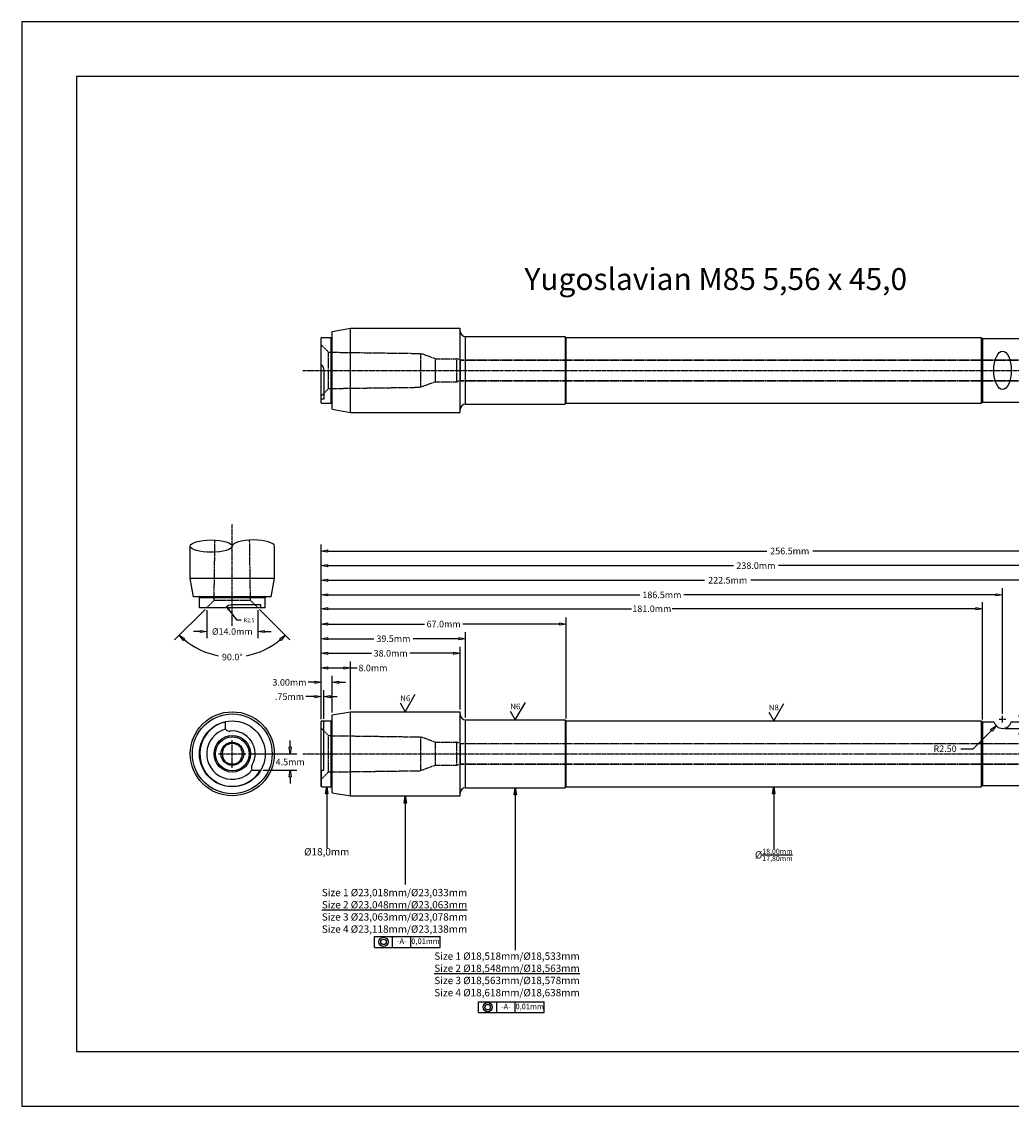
# Model space of a CAD drawing. Units: inches. Extents: x 0 to 420, y 0 to 297.
# Drawn here: x 0 to 271, y 0 to 297 of the extents above; entities that cross this region are included whole.
import ezdxf
from ezdxf.enums import TextEntityAlignment as Align

# ---------------------------------------------------------------- set-up
doc = ezdxf.new("R2010")
doc.units = ezdxf.units.IN
doc.header["$MEASUREMENT"] = 0
doc.linetypes.add('CENTER2', pattern=[1.125, 0.75, -0.125, 0.125, -0.125])
doc.linetypes.add('HIDDEN2', pattern=[0.1875, 0.125, -0.0625])
for name, color, linetype in [('CENTER', 1, 'CENTER2'), ('CENTERLINE', 1, 'CENTER2'), ('HIDDEN', 5, 'HIDDEN2'), ('TEXT', 5, 'Continuous')]:
    doc.layers.add(name, color=color, linetype=linetype)
doc.dimstyles.get("Standard").update_dxf_attribs({"dimscale": 10, "dimtxt": 0.18, "dimasz": 0.18, "dimexe": 0.18, "dimexo": 0.0625, "dimgap": 0.09, "dimtad": 0, "dimtih": 1, "dimtoh": 1, "dimdec": 4, "dimzin": 0, "dimdsep": 46, "dimtxsty": 'Standard', "dimblk": 'CLOSEDBLANK', "dimcen": 0.09, "dimadec": 4, "dimazin": 0, "dimtfac": 1, "dimtdec": 4, "dimtofl": 0, "dimtmove": 0, "dimatfit": 3, "dimldrblk": 'CLOSEDBLANK', "dimfxl": 0, "dimtolj": 1, "dimtzin": 0, "dimarcsym": 0})
doc.dimstyles.new('Standard$0', dxfattribs={"dimscale": 10, "dimtxt": 0.18, "dimasz": 0.18, "dimexe": 0.18, "dimexo": 0.0625, "dimgap": 0.09, "dimtad": 0, "dimtih": 1, "dimtoh": 1, "dimdec": 4, "dimzin": 4, "dimdsep": 46, "dimtxsty": 'Standard', "dimblk": 'CLOSEDBLANK', "dimcen": 0.09, "dimadec": 5, "dimazin": 1, "dimtfac": 1, "dimtdec": 4, "dimtofl": 0, "dimtmove": 0, "dimatfit": 3, "dimldrblk": 'CLOSEDBLANK', "dimfxl": 0, "dimtolj": 1, "dimtzin": 0, "dimarcsym": 0})

# ---------------------------------------------------------------- blocks, each defined once
blk = doc.blocks.new('_ClosedBlank')
at = {"color": 0, "linetype": 'ByBlock', "lineweight": -2}
for p, q in [((-1, 0.17), (0, 0)), ((-1, 0.17), (-1, -0.17)), ((0, 0), (-1, -0.17))]:
    blk.add_line(p, q, dxfattribs=at)
blk = doc.blocks.new('*D7')
at = {"color": 0, "lineweight": -2}
for p, q in [((80.2, 116.1), (78.4, 116.1)), ((82, 106.05), (82, 117.9)), ((85, 107.8), (85, 117.9)), ((86.8, 116.1), (88.6, 116.1))]:
    blk.add_line(p, q, dxfattribs=at)
at = {"layer": 'Defpoints', "color": 0}
for p in [(85, 116.1), (85, 107.18), (82, 105.43)]:
    blk.add_point(p, dxfattribs=at)
at = {"color": 0, "lineweight": -2, "xscale": 1.8, "yscale": 1.8, "zscale": 1.8}
blk.add_blockref('_ClosedBlank', (82, 116.1), dxfattribs=at)
at = {"color": 0, "lineweight": -2, "xscale": 1.8, "yscale": 1.8, "zscale": 1.8, "rotation": 180}
blk.add_blockref('_ClosedBlank', (85, 116.1), dxfattribs=at)
at = {"color": 0, "insert": (73.3, 116.1), "char_height": 1.8, "attachment_point": 5}
blk.add_mtext('\\A1;3.00mm', dxfattribs=at)
blk = doc.blocks.new('*D8')
at = {"color": 0, "lineweight": -2}
for p, q in [((82, 106.05), (82, 121.83)), ((90, 108.69), (90, 121.83)), ((83.8, 120.03), (88.2, 120.03)), ((90, 120.03), (91.8, 120.03))]:
    blk.add_line(p, q, dxfattribs=at)
at = {"layer": 'Defpoints', "color": 0}
for p in [(90, 120.03), (90, 108.06), (82, 105.43)]:
    blk.add_point(p, dxfattribs=at)
at = {"color": 0, "lineweight": -2, "xscale": 1.8, "yscale": 1.8, "zscale": 1.8, "rotation": 180}
blk.add_blockref('_ClosedBlank', (82, 120.03), dxfattribs=at)
at = {"color": 0, "lineweight": -2, "xscale": 1.8, "yscale": 1.8, "zscale": 1.8}
blk.add_blockref('_ClosedBlank', (90, 120.03), dxfattribs=at)
at = {"color": 0, "insert": (96.15, 120.03), "char_height": 1.8, "attachment_point": 5}
blk.add_mtext('\\A1;8.0mm', dxfattribs=at)
blk = doc.blocks.new('*D9')
at = {"color": 0, "lineweight": -2}
for p, q in [((82, 106.05), (82, 125.86)), ((120, 108.69), (120, 125.86)), ((83.8, 124.06), (95.75, 124.06)), ((118.2, 124.06), (106.25, 124.06))]:
    blk.add_line(p, q, dxfattribs=at)
at = {"layer": 'Defpoints', "color": 0}
for p in [(120, 124.06), (120, 108.06), (82, 105.43)]:
    blk.add_point(p, dxfattribs=at)
at = {"color": 0, "lineweight": -2, "xscale": 1.8, "yscale": 1.8, "zscale": 1.8, "rotation": 180}
blk.add_blockref('_ClosedBlank', (82, 124.06), dxfattribs=at)
at = {"color": 0, "lineweight": -2, "xscale": 1.8, "yscale": 1.8, "zscale": 1.8}
blk.add_blockref('_ClosedBlank', (120, 124.06), dxfattribs=at)
at = {"color": 0, "insert": (101, 124.06), "char_height": 1.8, "attachment_point": 5}
blk.add_mtext('\\A1;38.0mm', dxfattribs=at)
blk = doc.blocks.new('*D10')
at = {"color": 0, "lineweight": -2}
for p, q in [((82, 106.05), (82, 129.85)), ((83.8, 128.05), (96.35, 128.05)), ((119.7, 128.05), (107.15, 128.05)), ((121.5, 106.43), (121.5, 129.85))]:
    blk.add_line(p, q, dxfattribs=at)
at = {"layer": 'Defpoints', "color": 0}
for p in [(82, 128.05), (82, 105.43), (121.5, 105.8)]:
    blk.add_point(p, dxfattribs=at)
at = {"color": 0, "lineweight": -2, "xscale": 1.8, "yscale": 1.8, "zscale": 1.8, "rotation": 180}
blk.add_blockref('_ClosedBlank', (82, 128.05), dxfattribs=at)
at = {"color": 0, "lineweight": -2, "xscale": 1.8, "yscale": 1.8, "zscale": 1.8}
blk.add_blockref('_ClosedBlank', (121.5, 128.05), dxfattribs=at)
at = {"color": 0, "insert": (101.75, 128.05), "char_height": 1.8, "attachment_point": 5}
blk.add_mtext('\\A1;39.5mm', dxfattribs=at)
blk = doc.blocks.new('*D11')
at = {"color": 0, "lineweight": -2}
for p, q in [((82, 106.05), (82, 133.85)), ((149, 106.15), (149, 133.85)), ((83.8, 132.05), (110.25, 132.05)), ((147.2, 132.05), (120.75, 132.05))]:
    blk.add_line(p, q, dxfattribs=at)
at = {"layer": 'Defpoints', "color": 0}
for p in [(82, 132.05), (82, 105.43), (149, 105.53)]:
    blk.add_point(p, dxfattribs=at)
at = {"color": 0, "lineweight": -2, "xscale": 1.8, "yscale": 1.8, "zscale": 1.8, "rotation": 180}
blk.add_blockref('_ClosedBlank', (82, 132.05), dxfattribs=at)
at = {"color": 0, "lineweight": -2, "xscale": 1.8, "yscale": 1.8, "zscale": 1.8}
blk.add_blockref('_ClosedBlank', (149, 132.05), dxfattribs=at)
at = {"color": 0, "insert": (115.5, 132.05), "char_height": 1.8, "attachment_point": 5}
blk.add_mtext('\\A1;67.0mm', dxfattribs=at)
blk = doc.blocks.new('*D12')
at = {"color": 0, "lineweight": -2}
for p, q in [((82, 106.09), (82, 138.04)), ((263, 105.89), (263, 138.04)), ((83.8, 136.24), (166.95, 136.24)), ((261.2, 136.24), (178.05, 136.24))]:
    blk.add_line(p, q, dxfattribs=at)
at = {"layer": 'Defpoints', "color": 0}
for p in [(82, 136.24), (82, 105.47), (263, 105.27)]:
    blk.add_point(p, dxfattribs=at)
at = {"color": 0, "lineweight": -2, "xscale": 1.8, "yscale": 1.8, "zscale": 1.8, "rotation": 180}
blk.add_blockref('_ClosedBlank', (82, 136.24), dxfattribs=at)
at = {"color": 0, "lineweight": -2, "xscale": 1.8, "yscale": 1.8, "zscale": 1.8}
blk.add_blockref('_ClosedBlank', (263, 136.24), dxfattribs=at)
at = {"color": 0, "insert": (172.5, 136.24), "char_height": 1.8, "attachment_point": 5}
blk.add_mtext('\\A1;181.0mm', dxfattribs=at)
blk = doc.blocks.new('*D13')
at = {"color": 0, "lineweight": -2}
for p, q in [((82, 106.05), (82, 141.85)), ((83.8, 140.05), (169.25, 140.05)), ((266.7, 140.05), (181.25, 140.05)), ((268.5, 107.47), (268.5, 141.85))]:
    blk.add_line(p, q, dxfattribs=at)
at = {"layer": 'Defpoints', "color": 0}
for p in [(82, 140.05), (82, 105.43), (268.5, 106.85)]:
    blk.add_point(p, dxfattribs=at)
at = {"color": 0, "lineweight": -2, "xscale": 1.8, "yscale": 1.8, "zscale": 1.8, "rotation": 180}
blk.add_blockref('_ClosedBlank', (82, 140.05), dxfattribs=at)
at = {"color": 0, "lineweight": -2, "xscale": 1.8, "yscale": 1.8, "zscale": 1.8}
blk.add_blockref('_ClosedBlank', (268.5, 140.05), dxfattribs=at)
at = {"color": 0, "insert": (175.25, 140.05), "char_height": 1.8, "attachment_point": 5}
blk.add_mtext('\\A1;186.5mm', dxfattribs=at)
blk = doc.blocks.new('*D14')
at = {"color": 0, "lineweight": -2}
for p, q in [((82, 106.05), (82, 145.85)), ((304.5, 105.89), (304.5, 145.85)), ((83.8, 144.05), (186.95, 144.05)), ((302.7, 144.05), (199.55, 144.05))]:
    blk.add_line(p, q, dxfattribs=at)
at = {"layer": 'Defpoints', "color": 0}
for p in [(82, 144.05), (82, 105.43), (304.5, 105.27)]:
    blk.add_point(p, dxfattribs=at)
at = {"color": 0, "lineweight": -2, "xscale": 1.8, "yscale": 1.8, "zscale": 1.8, "rotation": 180}
blk.add_blockref('_ClosedBlank', (82, 144.05), dxfattribs=at)
at = {"color": 0, "lineweight": -2, "xscale": 1.8, "yscale": 1.8, "zscale": 1.8}
blk.add_blockref('_ClosedBlank', (304.5, 144.05), dxfattribs=at)
at = {"color": 0, "insert": (193.25, 144.05), "char_height": 1.8, "attachment_point": 5}
blk.add_mtext('\\A1;222.5mm', dxfattribs=at)
blk = doc.blocks.new('*D17')
at = {"color": 0, "lineweight": -2}
for p, q in [((82, 106.05), (82, 113.98)), ((82.75, 106.06), (82.75, 113.98)), ((80.2, 112.18), (77.8, 112.18)), ((84.55, 112.18), (86.35, 112.18))]:
    blk.add_line(p, q, dxfattribs=at)
at = {"layer": 'Defpoints', "color": 0}
for p in [(82.75, 112.18), (82, 105.43), (82.75, 105.43)]:
    blk.add_point(p, dxfattribs=at)
at = {"color": 0, "lineweight": -2, "xscale": 1.8, "yscale": 1.8, "zscale": 1.8}
blk.add_blockref('_ClosedBlank', (82, 112.18), dxfattribs=at)
at = {"color": 0, "lineweight": -2, "xscale": 1.8, "yscale": 1.8, "zscale": 1.8, "rotation": 180}
blk.add_blockref('_ClosedBlank', (82.75, 112.18), dxfattribs=at)
at = {"color": 0, "insert": (73.3, 112.18), "char_height": 1.8, "attachment_point": 5}
blk.add_mtext('\\A1;.75mm', dxfattribs=at)
blk = doc.blocks.new('*D18')
at = {"color": 0, "lineweight": -2}
for p, q in [((73.5, 98.33), (73.5, 100.13)), ((62.08, 96.53), (75.3, 96.53)), ((66.07, 92.03), (75.3, 92.03)), ((73.5, 90.23), (73.5, 88.43))]:
    blk.add_line(p, q, dxfattribs=at)
at = {"layer": 'Defpoints', "color": 0}
for p in [(61.46, 96.53), (73.5, 96.53), (65.44, 92.03)]:
    blk.add_point(p, dxfattribs=at)
at = {"color": 0, "lineweight": -2, "xscale": 1.8, "yscale": 1.8, "zscale": 1.8}
for p, rotation in [((73.5, 96.53), 270), ((73.5, 92.03), 90)]:
    blk.add_blockref('_ClosedBlank', p, dxfattribs=dict(at, rotation=rotation))
at = {"color": 0, "insert": (73.5, 94.28), "char_height": 1.8, "attachment_point": 5}
blk.add_mtext('\\A1;4.5mm', dxfattribs=at)
blk = doc.blocks.new('*D19')
at = {"color": 0, "lineweight": -2}
for p, q in [((58.99, 133.09), (56.78, 135.95)), ((60.07, 133.09), (58.99, 133.09))]:
    blk.add_line(p, q, dxfattribs=at)
at = {"layer": 'Defpoints', "color": 0}
for p in [(56.12, 136.8), (57.65, 134.83)]:
    blk.add_point(p, dxfattribs=at)
at = {"color": 0, "lineweight": -2, "xscale": 1.08, "yscale": 1.08, "zscale": 1.08, "rotation": 127.7379653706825}
blk.add_blockref('_ClosedBlank', (56.12, 136.8), dxfattribs=at)
at = {"color": 0, "insert": (62.23, 133.09), "char_height": 1.08, "attachment_point": 5}
blk.add_mtext('\\A1;R2.5', dxfattribs=at)
blk = doc.blocks.new('*D22')
at = {"color": 0, "lineweight": -2}
for p, q in [((82, 106.05), (82, 149.85)), ((319.98, 106.18), (319.98, 149.85)), ((83.8, 148.05), (194.84, 148.05)), ((318.18, 148.05), (207.14, 148.05))]:
    blk.add_line(p, q, dxfattribs=at)
at = {"layer": 'Defpoints', "color": 0}
for p in [(82, 148.05), (82, 105.43), (319.98, 105.55)]:
    blk.add_point(p, dxfattribs=at)
at = {"color": 0, "lineweight": -2, "xscale": 1.8, "yscale": 1.8, "zscale": 1.8, "rotation": 180}
blk.add_blockref('_ClosedBlank', (82, 148.05), dxfattribs=at)
at = {"color": 0, "lineweight": -2, "xscale": 1.8, "yscale": 1.8, "zscale": 1.8}
blk.add_blockref('_ClosedBlank', (319.98, 148.05), dxfattribs=at)
at = {"color": 0, "insert": (200.99, 148.05), "char_height": 1.8, "attachment_point": 5}
blk.add_mtext('\\A1;238.0mm', dxfattribs=at)
blk = doc.blocks.new('*D23')
at = {"color": 0, "lineweight": -2}
for p, q in [((273.39, 107.07), (273.39, 113.24)), ((273.39, 113.24), (275.19, 113.24)), ((271.66, 105.27), (275.19, 105.27)), ((269.12, 103.49), (275.19, 103.49)), ((273.39, 101.69), (273.39, 99.89))]:
    blk.add_line(p, q, dxfattribs=at)
at = {"layer": 'Defpoints', "color": 0}
for p in [(271.04, 105.27), (273.39, 105.27), (268.5, 103.49)]:
    blk.add_point(p, dxfattribs=at)
at = {"color": 0, "lineweight": -2, "xscale": 1.8, "yscale": 1.8, "zscale": 1.8}
for p, rotation in [((273.39, 105.27), 270), ((273.39, 103.49), 90)]:
    blk.add_blockref('_ClosedBlank', p, dxfattribs=dict(at, rotation=rotation))
at = {"color": 0, "insert": (280.29, 113.24), "char_height": 1.8, "attachment_point": 5}
blk.add_mtext('\\A1;1.78mm', dxfattribs=at)
blk = doc.blocks.new('*D24')
at = {"color": 0, "lineweight": -2}
for p, q in [((260.42, 97.91), (265.46, 102.95)), ((257.12, 97.91), (260.42, 97.91))]:
    blk.add_line(p, q, dxfattribs=at)
at = {"layer": 'Defpoints', "color": 0}
for p in [(266.73, 104.22), (268.5, 105.99)]:
    blk.add_point(p, dxfattribs=at)
at = {"color": 0, "lineweight": -2, "xscale": 1.8, "yscale": 1.8, "zscale": 1.8, "rotation": 44.99999999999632}
blk.add_blockref('_ClosedBlank', (266.73, 104.22), dxfattribs=at)
at = {"color": 0, "insert": (252.77, 97.91), "char_height": 1.8, "attachment_point": 5}
blk.add_mtext('\\A1;R2.50', dxfattribs=at)
blk = doc.blocks.new('*D25')
at = {"color": 0, "lineweight": -2}
for p, q in [((82, 106.05), (82, 153.85)), ((83.8, 152.05), (203.95, 152.05)), ((336.7, 152.05), (216.55, 152.05)), ((338.5, 104.18), (338.5, 153.85))]:
    blk.add_line(p, q, dxfattribs=at)
at = {"layer": 'Defpoints', "color": 0}
for p in [(82, 152.05), (82, 105.43), (338.5, 103.55)]:
    blk.add_point(p, dxfattribs=at)
at = {"color": 0, "lineweight": -2, "xscale": 1.8, "yscale": 1.8, "zscale": 1.8, "rotation": 180}
blk.add_blockref('_ClosedBlank', (82, 152.05), dxfattribs=at)
at = {"color": 0, "lineweight": -2, "xscale": 1.8, "yscale": 1.8, "zscale": 1.8}
blk.add_blockref('_ClosedBlank', (338.5, 152.05), dxfattribs=at)
at = {"color": 0, "insert": (210.25, 152.05), "char_height": 1.8, "attachment_point": 5}
blk.add_mtext('\\A1;256.5mm', dxfattribs=at)
blk = doc.blocks.new('*D26')
at = {"color": 0, "lineweight": -2}
for p, q in [((50.65, 135.9), (50.65, 128.21)), ((64.65, 135.9), (64.65, 128.21)), ((48.85, 130.01), (47.05, 130.01)), ((66.45, 130.01), (68.25, 130.01))]:
    blk.add_line(p, q, dxfattribs=at)
at = {"layer": 'Defpoints', "color": 0}
for p in [(50.65, 136.53), (64.65, 136.53), (64.65, 130.01)]:
    blk.add_point(p, dxfattribs=at)
at = {"color": 0, "lineweight": -2, "xscale": 1.8, "yscale": 1.8, "zscale": 1.8}
blk.add_blockref('_ClosedBlank', (50.65, 130.01), dxfattribs=at)
at = {"color": 0, "lineweight": -2, "xscale": 1.8, "yscale": 1.8, "zscale": 1.8, "rotation": 180}
blk.add_blockref('_ClosedBlank', (64.65, 130.01), dxfattribs=at)
at = {"color": 0, "insert": (57.65, 130.01), "char_height": 1.8, "attachment_point": 5}
blk.add_mtext('\\A1;%%C14.0mm', dxfattribs=at)
blk = doc.blocks.new('*D27')
at = {"color": 0, "lineweight": -2}
for p, q in [((50.21, 136.08), (41.87, 127.75)), ((65.09, 136.08), (73.43, 127.75))]:
    blk.add_line(p, q, dxfattribs=at)
for start, end in [(230.0298, 259.0388), (280.9612, 309.9702)]:
    blk.add_arc((57.65, 143.53), 20.51, start, end, dxfattribs=at)
at = {"layer": 'Defpoints', "color": 0}
for p in [(52.67, 138.55), (62.63, 138.55), (50.65, 136.53), (64.65, 136.53), (52.34, 123.71)]:
    blk.add_point(p, dxfattribs=at)
at = {"color": 0, "lineweight": -2, "xscale": 1.8, "yscale": 1.8, "zscale": 1.8}
for p, rotation in [((43.15, 129.02), 137.5149116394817), ((72.15, 129.02), 42.48508836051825)]:
    blk.add_blockref('_ClosedBlank', p, dxfattribs=dict(at, rotation=rotation))
at = {"color": 0, "insert": (57.65, 123.01), "char_height": 1.8, "attachment_point": 5}
blk.add_mtext('\\A1;90.0°', dxfattribs=at)

msp = doc.modelspace()

# ---------------------------------------------------------------- linework, layer by layer
for p, q in [((84.99996, 212.17839), (89.99996, 213.06003)), ((84.99996, 190.87166), (84.99996, 212.17839)), ((89.99996, 213.06003), (119.99996, 213.06003)), ((89.99996, 189.99003), (89.99996, 213.06003)), ((119.99996, 189.99003), (119.99996, 213.06003)), ((81.99996, 192.62503), (81.99996, 210.42503)), ((82.09996, 210.52503), (84.74996, 210.52503)), ((84.74996, 192.52503), (84.74996, 210.52503)), ((121.49996, 192.25003), (121.49996, 210.80003)), ((121.49996, 210.80003), (148.74996, 210.80003)), ((148.74996, 210.80003), (148.74996, 192.25003)), ((148.99996, 210.52503), (262.75121, 210.52503)), ((148.99996, 192.52503), (148.99996, 210.52503)), ((262.75121, 192.52503), (262.75121, 210.52503)), ((263.00121, 210.22503), (263.00121, 192.82503)), ((263.00121, 210.22503), (304.49996, 210.22503)), ((82.79996, 193.7308), (82.79996, 201.52503)), ((81.99996, 193.7308), (82.79996, 193.7308)), ((82.09996, 192.52503), (84.74996, 192.52503)), ((84.99996, 190.87166), (89.99996, 189.99003)), ((121.49996, 192.25003), (148.74996, 192.25003)), ((148.99996, 192.52503), (262.75121, 192.52503)), ((263.00121, 192.82503), (304.49996, 192.82503)), ((89.99996, 189.99003), (119.99996, 189.99003)), ((46.11496, 144.52503), (46.11496, 153.39189)), ((69.18496, 144.52503), (69.18496, 153.39189)), ((69.18496, 144.52503), (46.11496, 144.52503)), ((46.9966, 139.52503), (46.11496, 144.52503)), ((68.30333, 139.52503), (69.18496, 144.52503)), ((68.30333, 139.52503), (46.9966, 139.52503)), ((48.64996, 136.62503), (48.64996, 139.27503)), ((66.64996, 139.27503), (48.64996, 139.27503)), ((65.44419, 137.32503), (57.64996, 137.32503)), ((65.44419, 136.52503), (65.44419, 137.32503)), ((66.64996, 136.62503), (66.64996, 139.27503)), ((66.54996, 136.52503), (48.74996, 136.52503)), ((103.62514, 110.44128), (104.99996, 108.06003)), ((104.99996, 108.06003), (107.74959, 112.82253)), ((135.12496, 105.80003), (137.87459, 110.56253)), ((205.87559, 105.52503), (208.62522, 110.28753)), ((84.99996, 107.17839), (89.99996, 108.06003)), ((84.99996, 85.87166), (84.99996, 107.17839)), ((89.99996, 108.06003), (119.99996, 108.06003)), ((89.99996, 84.99003), (89.99996, 108.06003)), ((119.99996, 84.99003), (119.99996, 108.06003)), ((133.75015, 108.18128), (135.12496, 105.80003)), ((204.50077, 107.90628), (205.87559, 105.52503)), ((55.81693, 103.28077), (55.81693, 105.30811)), ((81.99996, 87.62503), (81.99996, 105.42503)), ((82.09996, 105.52503), (84.74996, 105.52503)), ((82.74996, 92.02503), (82.74996, 105.43705)), ((84.74996, 87.52503), (84.74996, 105.52503)), ((121.49996, 87.25003), (121.49996, 105.80003)), ((121.49996, 105.80003), (148.74996, 105.80003)), ((148.74996, 105.80003), (148.74996, 87.25003)), ((148.99996, 105.52503), (262.75121, 105.52503)), ((148.99996, 87.52503), (148.99996, 105.52503)), ((262.75121, 87.52503), (262.75121, 105.52503)), ((263.00121, 105.26503), (263.00121, 87.82503)), ((263.00121, 105.26503), (266.10649, 105.26503)), ((270.89343, 105.26503), (304.49996, 105.26503)), ((82.74996, 102.77503), (81.99996, 103.52503)), ((63.01186, 92.02503), (65.44419, 92.02503)), ((81.99996, 92.02503), (82.74996, 92.02503)), ((82.09996, 87.52503), (82.09996, 92.02503)), ((82.09996, 87.52503), (84.74996, 87.52503)), ((121.49996, 87.25003), (148.74996, 87.25003)), ((148.99996, 87.52503), (262.75121, 87.52503)), ((263.00121, 87.82503), (304.49996, 87.82503)), ((84.99996, 85.87166), (89.99996, 84.99003)), ((89.99996, 84.99003), (119.99996, 84.99003))]:
    msp.add_line(p, q)
for points in [[(0, 0), (420, 0), (420, 297), (0, 297)], [(15, 15), (405, 15), (405, 282), (15, 282)]]:
    msp.add_lwpolyline(points, close=True)
for radius in [11.5, 10.9211, 9, 5.0063, 4.625, 3.145]:
    msp.add_circle((57.64996, 96.52503), radius)
for centre, radius, start, end in [((121.49996, 212.30003), 1.5, 180, 270), ((82.09996, 210.42503), 0.1, 90, 180), ((84.74996, 210.77503), 0.25, 270, 0), ((148.99996, 210.77503), 0.25, 180, 270), ((263.00121, 210.47503), 0.25, 180, 270), ((80.79996, 201.52503), 2, 0, 53.1301024), ((82.09996, 192.62503), 0.1, 180, 270), ((84.74996, 192.27503), 0.25, 0, 90), ((121.49996, 190.75003), 1.5, 90, 180), ((148.99996, 192.27503), 0.25, 90, 180), ((263.00121, 192.57503), 0.25, 90, 180), ((48.39996, 139.27503), 0.25, 0, 90), ((48.74996, 136.62503), 0.1, 180, 270), ((57.64996, 134.82503), 2.5, 90, 137.156357), ((66.54996, 136.62503), 0.1, 270, 360), ((66.89996, 139.27503), 0.25, 90, 180), ((121.49996, 107.30003), 1.5, 180, 270), ((57.64996, 96.52503), 8.9, 101.885612, 329.6276163), ((82.09996, 105.42503), 0.1, 90, 180), ((84.74996, 105.77503), 0.25, 270, 0), ((148.99996, 105.77503), 0.25, 180, 270), ((263.00121, 105.51503), 0.25, 180, 270), ((268.49996, 105.98703), 2.5, 196.7861274, 343.2138726), ((57.64996, 96.52503), 7, 105.1805438, 319.9947991), ((56.92145, 104.13582), 1.39681, 217.7449003, 277.6444066), ((57.64996, 96.52503), 6.25, 330.7, 95.9540752), ((57.64996, 96.52503), 2.85, 119.723042, 150.2785778), ((56.28649, 98.91322), 0.1, 46.1895335, 119.723042), ((57.64996, 96.52503), 2.78, 62.2554388, 117.7461811), ((59.01336, 98.91326), 0.1, 60.2785778, 133.8120863), ((57.64996, 96.52503), 2.85, 29.723042, 60.2785778), ((57.64996, 96.52503), 2.78, 152.2554388, 207.7461811), ((55.26173, 97.88843), 0.1, 150.2785778, 223.8120863), ((55.26177, 95.16156), 0.1, 136.1895335, 209.723042), ((57.64996, 96.52503), 2.85, 209.723042, 240.2785778), ((57.64996, 96.52503), 2.85, 299.723042, 330.2785778), ((60.03815, 97.8885), 0.1, 316.1895335, 29.723042), ((57.64996, 96.52503), 2.78, 332.2554388, 27.7461811), ((60.03819, 95.16162), 0.1, 330.2785778, 43.8120863), ((56.28656, 94.1368), 0.1, 240.2785778, 313.8120863), ((57.64996, 96.52503), 2.78, 242.2554388, 297.7461811), ((59.01343, 94.13684), 0.1, 226.1895335, 299.723042), ((64.2927, 92.67096), 1.43329, 146.2913703, 206.7411104), ((82.09996, 87.62503), 0.1, 180, 270), ((84.74996, 87.27503), 0.25, 0, 90), ((121.49996, 85.75003), 1.5, 90, 180), ((148.99996, 87.27503), 0.25, 90, 180), ((263.00121, 87.57503), 0.25, 90, 180)]:
    msp.add_arc(centre, radius, start, end)
for centre, major_axis, ratio in [((268.49996, 201.52503), (0, -5.2703), 0.454143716), ((51.88246, 153.39189), (-5.7675, 0), 0.291449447)]:
    msp.add_ellipse(centre, major_axis=major_axis, ratio=ratio)
for centre, major_axis, ratio, start_param, end_param in [((63.41746, 153.39189), (-5.7675, 0), 0.291449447, 3.141592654, 6.283185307), ((81.99996, 105.43079), (0.75041, 0.00318), 0.126149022, -0.033582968, 1.436603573)]:
    msp.add_ellipse(centre, major_axis=major_axis, ratio=ratio, start_param=start_param, end_param=end_param)
at = {"layer": 'CENTER'}
for p, q in [((267.59996, 105.98703), (269.39996, 105.98703)), ((268.49996, 105.08703), (268.49996, 106.88703))]:
    msp.add_line(p, q, dxfattribs=at)
at = {"layer": 'CENTERLINE'}
for p, q in [((76.99996, 201.52503), (343.49996, 201.52503)), ((57.64996, 131.52503), (57.64996, 159.42228)), ((57.64996, 92.71503), (57.64996, 100.33503)), ((53.83996, 96.52503), (61.45996, 96.52503)), ((76.99996, 96.52503), (343.49996, 96.52503))]:
    msp.add_line(p, q, dxfattribs=at)
at = {"layer": 'HIDDEN'}
for p, q in [((81.99996, 208.52503), (84.02196, 206.50302)), ((84.02196, 206.50303), (109.24996, 206.15003)), ((84.02196, 196.54703), (84.02196, 206.50303)), ((109.24996, 196.90017), (109.24996, 206.15003)), ((113.24997, 204.67003), (109.25001, 206.15002)), ((113.24997, 204.67003), (119.06996, 204.67003)), ((113.24997, 198.25204), (113.24997, 204.67002)), ((119.06996, 198.38003), (119.06996, 204.67003)), ((120.13754, 204.37503), (119.06996, 204.67003)), ((120.13754, 198.67503), (120.13754, 204.37503)), ((120.13754, 204.37503), (338.49996, 204.37503)), ((120.13754, 204.30503), (338.49996, 204.30503)), ((81.99996, 194.52503), (84.02196, 196.54703)), ((84.02196, 196.54703), (109.24998, 196.90017)), ((113.24997, 198.38003), (109.25001, 196.90004)), ((113.24997, 198.38003), (119.06996, 198.38003)), ((120.13754, 198.67503), (119.06999, 198.3799)), ((120.13754, 198.74503), (338.49996, 198.74503)), ((120.13754, 198.67503), (338.49996, 198.67503)), ((52.67196, 138.54703), (52.90282, 155.04631)), ((62.62796, 138.54703), (62.397, 155.0463)), ((50.64996, 136.52503), (52.67196, 138.54703)), ((62.62796, 138.54703), (52.67196, 138.54703)), ((64.64996, 136.52503), (62.62796, 138.54703)), ((82.74996, 102.77503), (84.02196, 101.50302)), ((84.02196, 101.50303), (109.24996, 101.15003)), ((84.02196, 91.54703), (84.02196, 101.50303)), ((109.24996, 91.90017), (109.24996, 101.15003)), ((113.24997, 99.67003), (109.25001, 101.15002)), ((113.24997, 99.67003), (119.06996, 99.67003)), ((113.24997, 93.25204), (113.24997, 99.67002)), ((119.06996, 93.38003), (119.06996, 99.67003)), ((120.13754, 99.37503), (119.06996, 99.67003)), ((120.13754, 93.67503), (120.13754, 99.37503)), ((120.13754, 99.37503), (338.49996, 99.37503)), ((120.13754, 99.30503), (338.49996, 99.30503)), ((113.24997, 93.38003), (109.25001, 91.90004)), ((113.24997, 93.38003), (119.06996, 93.38003)), ((120.13754, 93.67503), (119.06999, 93.3799)), ((120.13754, 93.74503), (338.49996, 93.74503)), ((120.13754, 93.67503), (338.49996, 93.67503)), ((81.99996, 89.52503), (84.02196, 91.54703)), ((84.02196, 91.54703), (109.24998, 91.90017))]:
    msp.add_line(p, q, dxfattribs=at)
for p in [(119.06996, 204.67003), (119.06996, 198.38003), (119.06996, 99.67003), (119.06996, 93.38003)]:
    msp.add_point(p, dxfattribs=at)
at = {"layer": 'TEXT', "color": 7}
for p, q in [((96.5396, 43.525), (96.5396, 46.525)), ((96.5396, 46.525), (101.5396, 46.525)), ((101.5396, 46.525), (106.5396, 46.525)), ((101.5396, 43.525), (101.5396, 46.525)), ((106.5396, 46.525), (114.5396, 46.525)), ((106.5396, 43.525), (106.5396, 46.525)), ((114.5396, 43.525), (114.5396, 46.525)), ((96.5396, 43.525), (101.5396, 43.525)), ((101.5396, 43.525), (106.5396, 43.525)), ((106.5396, 43.525), (114.5396, 43.525)), ((125.04924, 25.6422), (125.04924, 28.6422)), ((125.04924, 28.6422), (130.04924, 28.6422)), ((130.04924, 28.6422), (135.04924, 28.6422)), ((130.04924, 25.6422), (130.04924, 28.6422)), ((135.04924, 28.6422), (143.04924, 28.6422)), ((135.04924, 25.6422), (135.04924, 28.6422)), ((143.04924, 25.6422), (143.04924, 28.6422)), ((125.04924, 25.6422), (130.04924, 25.6422)), ((130.04924, 25.6422), (135.04924, 25.6422)), ((135.04924, 25.6422), (143.04924, 25.6422))]:
    msp.add_line(p, q, dxfattribs=at)
for centre, radius in [((99.0396, 45.025), 1.25), ((99.0396, 45.025), 0.75), ((127.54924, 27.1422), 1.25), ((127.54924, 27.1422), 0.75)]:
    msp.add_circle(centre, radius, dxfattribs=at)

# ---------------------------------------------------------------- texts
msp.add_text('Yugoslavian M85 5,56 x 45,0', height=6).set_placement((190, 226.525), align=Align.MIDDLE_CENTER)
for s, p in [('N6', (104.99996, 110.44128)), ('N6', (135.12496, 108.18128)), ('N8', (205.87559, 107.90628))]:
    msp.add_text(s, height=1.5875).set_placement(p, align=Align.BOTTOM_CENTER)
at = {"char_height": 2, "width": 10.5482646, "attachment_point": 2}
for s, insert in [('\\A1;%%C18,0mm', (83.49996, 70.69381)), ('\\A1;%%C{\\H0.7x;\\S18,00mm/17,80mm;}', (205.87431, 70.52503))]:
    msp.add_mtext(s, dxfattribs=dict(at, insert=insert))
at = {"layer": 'TEXT', "color": 7}
for s, insert, char_height, width, attachment_point in [('\\A1;Size 1 %%C23,018mm/%%C23,033mm\\P{\\LSize 2 %%C23,048mm/%%C23,063mm}\\PSize 3 %%C23,063mm/%%C23,078mm\\PSize 4 %%C23,118mm/%%C23,138mm', (82.15454, 59.525), 2, 48.5376086, 1), ('-A-', (104.0396, 45.025), 1.5, 1.19634, 5), ('0,01mm', (110.5396, 45.025), 1.5, 6.6720954, 5), ('\\A1;Size 1 %%C18,518mm/%%C18,533mm\\P{\\LSize 2 %%C18,548mm/%%C18,563mm}\\PSize 3 %%C18,563mm/%%C18,578mm\\PSize 4 %%C18,618mm/%%C18,638mm', (112.94139, 42.12518), 2, 48.5376086, 1), ('-A-', (132.54924, 27.1422), 1.5, 1.19634, 5), ('0,01mm', (139.04924, 27.1422), 1.5, 6.6720954, 5)]:
    msp.add_mtext(s, dxfattribs=dict(at, insert=insert, char_height=char_height, width=width, attachment_point=attachment_point))

# ---------------------------------------------------------------- dimensions: what is measured, and where the dimension line sits
for base, p1, p2, picture, middle in [((81.99996, 152.05003), (338.49996, 103.55003), (81.99996, 105.42503), '*D25', (210.24996, 152.05003)), ((81.99996, 148.05003), (319.982, 105.55003), (81.99996, 105.42503), '*D22', (200.99098, 148.05003)), ((81.99996, 144.05003), (304.49996, 105.26503), (81.99996, 105.42503), '*D14', (193.24996, 144.05003)), ((81.99996, 140.05003), (268.49996, 106.84703), (81.99996, 105.42503), '*D13', (175.24996, 140.05003)), ((81.99996, 136.24003), (263.00121, 105.26503), (81.99996, 105.46503), '*D12', (172.50059, 136.24003)), ((81.99996, 132.05003), (148.99996, 105.52503), (81.99996, 105.42503), '*D11', (115.49996, 132.05003)), ((81.99996, 128.05003), (121.49996, 105.80003), (81.99996, 105.42503), '*D10', (101.74996, 128.05003)), ((119.99996, 124.06003), (81.99996, 105.42503), (119.99996, 108.06003), '*D9', (100.99996, 124.06003)), ((89.99996, 120.02503), (81.99996, 105.42503), (89.99996, 108.06003), '*D8', (96.14996, 120.02503))]:
    dim = msp.add_linear_dim(base=base, p1=p1, p2=p2, dimstyle='Standard$0', override={"dimscale": 10, "dimdec": 1, "dimpost": 'mm', "dimblk1": 'ClosedBlank', "dimblk2": 'ClosedBlank', "dimsah": 1})
    dim.commit()
    dim.dimension.update_dxf_attribs({"geometry": picture, "text_midpoint": middle})
dim = msp.add_angular_dim_2l(base=(52.34138, 123.71315), line1=((64.64996, 136.52503), (62.62796, 138.54703)), line2=((50.64996, 136.52503), (52.67196, 138.54703)), dimstyle='Standard', override={"dimadec": 1})
dim.commit()
dim.dimension.update_dxf_attribs({"geometry": '*D27', "text_midpoint": (57.64996, 123.01426)})
for center, mpoint, override, picture, middle in [((57.64996, 134.82503), (56.11983, 136.80207), {"dimscale": 6, "dimdec": 1, "dimtmove": 1}, '*D19', (58.99376, 133.08874)), ((268.49996, 105.98703), (266.73219, 104.21926), {"dimdec": 2, "dimcen": 0}, '*D24', (252.77488, 97.91195))]:
    dim = msp.add_radius_dim(center=center, mpoint=mpoint, dimstyle='Standard', override=override)
    dim.commit()
    dim.dimension.update_dxf_attribs({"geometry": picture, "text_midpoint": middle, "dimtype": 164})
dim = msp.add_linear_dim(base=(64.64996, 130.00655), p1=(50.64996, 136.52503), p2=(64.64996, 136.52503), text='%%C<>', dimstyle='Standard$0', override={"dimdec": 1, "dimpost": 'mm'})
dim.commit()
dim.dimension.update_dxf_attribs({"geometry": '*D26', "text_midpoint": (57.64996, 130.00655)})
for base, p2, picture, middle in [((84.99996, 116.10003), (84.99996, 107.17839), '*D7', (73.29996, 116.10003)), ((82.74996, 112.17503), (82.74996, 105.43079), '*D17', (73.29996, 112.17503))]:
    dim = msp.add_linear_dim(base=base, p1=(81.99996, 105.42503), p2=p2, dimstyle='Standard$0', override={"dimscale": 10, "dimdec": 2, "dimpost": 'mm', "dimblk1": 'ClosedBlank', "dimblk2": 'ClosedBlank', "dimsah": 1})
    dim.commit()
    dim.dimension.update_dxf_attribs({"geometry": picture, "text_midpoint": middle, "dimtype": 160})
dim = msp.add_linear_dim(base=(273.38766, 105.26503), p1=(268.49996, 103.48703), p2=(271.03921, 105.26503), angle=90, dimstyle='Standard$0', override={"dimdec": 2, "dimpost": 'mm'})
dim.commit()
dim.dimension.update_dxf_attribs({"geometry": '*D23', "text_midpoint": (280.28766, 113.24372), "dimtype": 160})
dim = msp.add_linear_dim(base=(73.49721, 96.52503), p1=(65.44419, 92.02503), p2=(61.45996, 96.52503), angle=90, dimstyle='Standard$0', override={"dimdec": 1, "dimpost": 'mm'})
dim.commit()
dim.dimension.update_dxf_attribs({"geometry": '*D18', "text_midpoint": (73.49721, 94.27503)})

# ---------------------------------------------------------------- leaders
for points in [[(83.49996, 87.52503), (83.49996, 70.69381)], [(205.87431, 87.52503), (205.87431, 70.52503)]]:
    msp.add_leader(points, dimstyle='Standard', override={"dimscale": 1, "dimasz": 2, "dimgap": 0.09, "dimtad": 0, "dimldrblk": 'ClosedBlank'})
for points in [[(135.12496, 87.25003), (135.12496, 42.72779)], [(104.99996, 84.99003), (104.99996, 60.76401)]]:
    msp.add_leader(points, dimstyle='Standard', override={"dimscale": 1, "dimasz": 2, "dimgap": 0.09, "dimtad": 0, "dimldrblk": 'ClosedBlank'}, dxfattribs=at)

doc.saveas('drawing.dxf')
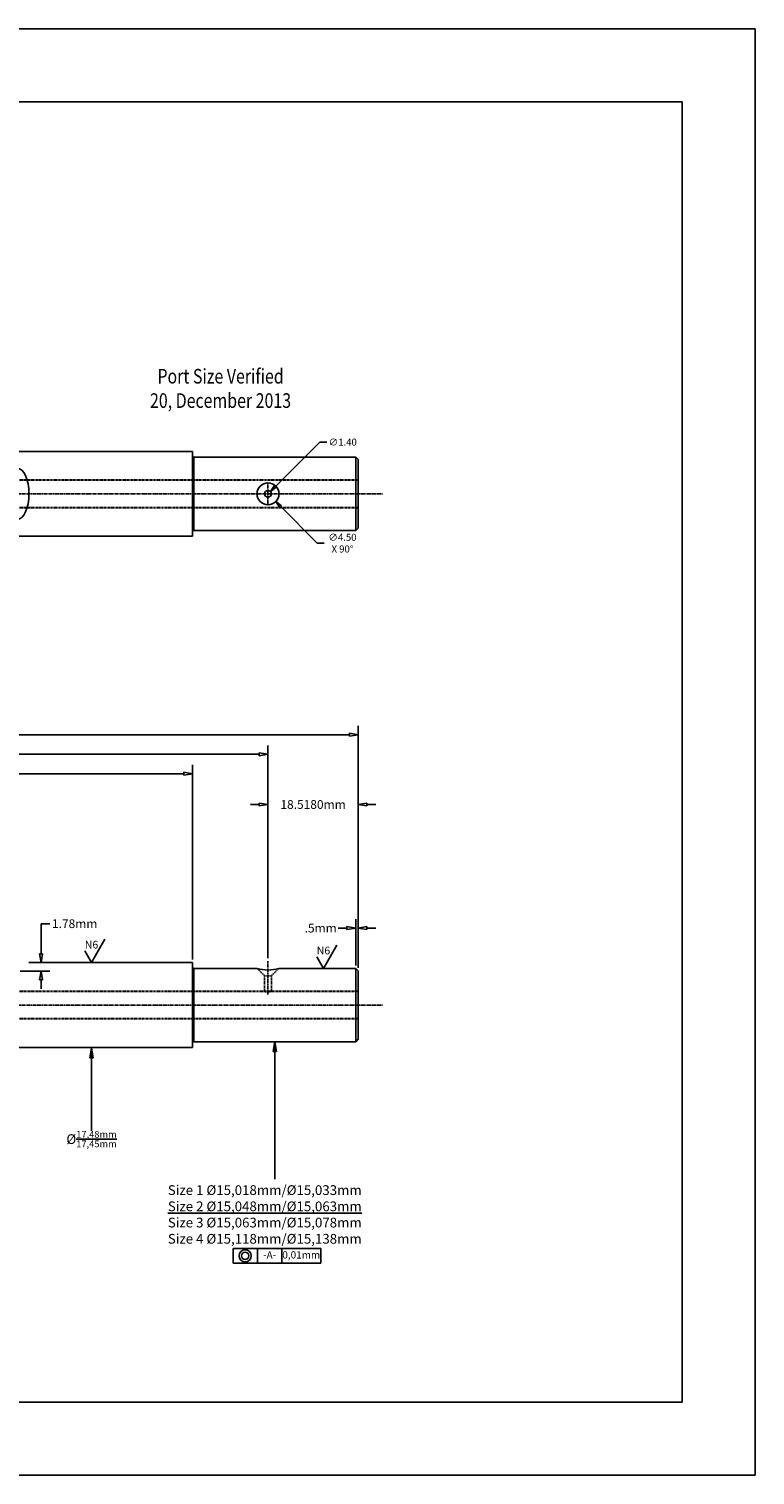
# Model space of a CAD drawing. Units: inches. Extents: x 0 to 420, y 0 to 297.
# Drawn here: x 271 to 420, y 0 to 297 of the extents above; entities that cross this region are included whole.
import ezdxf
from ezdxf.enums import TextEntityAlignment as Align

# ---------------------------------------------------------------- set-up
doc = ezdxf.new("R2010")
doc.units = ezdxf.units.IN
doc.header["$MEASUREMENT"] = 0
doc.linetypes.add('CENTER2', pattern=[1.125, 0.75, -0.125, 0.125, -0.125])
doc.linetypes.add('HIDDEN2', pattern=[0.1875, 0.125, -0.0625])
for name, color, linetype in [('CENTER', 1, 'CENTER2'), ('CENTERLINE', 1, 'CENTER2'), ('HIDDEN', 5, 'HIDDEN2'), ('TEXT', 5, 'Continuous')]:
    doc.layers.add(name, color=color, linetype=linetype)
doc.dimstyles.get("Standard").update_dxf_attribs({"dimscale": 10, "dimtxt": 0.18, "dimasz": 0.18, "dimexe": 0.18, "dimexo": 0.0625, "dimgap": 0.09, "dimtad": 0, "dimtih": 1, "dimtoh": 1, "dimdec": 4, "dimzin": 0, "dimdsep": 46, "dimtxsty": 'Standard', "dimblk": 'CLOSEDBLANK', "dimcen": 0.09, "dimadec": 4, "dimazin": 0, "dimtfac": 1, "dimtdec": 4, "dimtofl": 0, "dimtmove": 0, "dimatfit": 3, "dimldrblk": 'CLOSEDBLANK', "dimfxl": 0, "dimtolj": 1, "dimtzin": 0, "dimarcsym": 0})
doc.dimstyles.new('Standard$0', dxfattribs={"dimscale": 10, "dimtxt": 0.18, "dimasz": 0.18, "dimexe": 0.18, "dimexo": 0.0625, "dimgap": 0.09, "dimtad": 0, "dimtih": 1, "dimtoh": 1, "dimdec": 4, "dimzin": 4, "dimdsep": 46, "dimtxsty": 'Standard', "dimblk": 'CLOSEDBLANK', "dimcen": 0.09, "dimadec": 5, "dimazin": 1, "dimtfac": 1, "dimtdec": 4, "dimtofl": 0, "dimtmove": 0, "dimatfit": 3, "dimldrblk": 'CLOSEDBLANK', "dimfxl": 0, "dimtolj": 1, "dimtzin": 0, "dimarcsym": 0})

# ---------------------------------------------------------------- blocks, each defined once
blk = doc.blocks.new('_ClosedBlank')
at = {"color": 0, "linetype": 'ByBlock', "lineweight": -2}
for p, q in [((-1, 0.17), (0, 0)), ((-1, 0.17), (-1, -0.17)), ((0, 0), (-1, -0.17))]:
    blk.add_line(p, q, dxfattribs=at)
blk = doc.blocks.new('*D14')
at = {"color": 0, "lineweight": -2}
for p, q in [((82, 106.05), (82, 145.85)), ((304.5, 105.89), (304.5, 145.85)), ((83.8, 144.05), (186.95, 144.05)), ((302.7, 144.05), (199.55, 144.05))]:
    blk.add_line(p, q, dxfattribs=at)
at = {"layer": 'Defpoints', "color": 0}
for p in [(82, 144.05), (82, 105.43), (304.5, 105.27)]:
    blk.add_point(p, dxfattribs=at)
at = {"color": 0, "lineweight": -2, "xscale": 1.8, "yscale": 1.8, "zscale": 1.8, "rotation": 180}
blk.add_blockref('_ClosedBlank', (82, 144.05), dxfattribs=at)
at = {"color": 0, "lineweight": -2, "xscale": 1.8, "yscale": 1.8, "zscale": 1.8}
blk.add_blockref('_ClosedBlank', (304.5, 144.05), dxfattribs=at)
at = {"color": 0, "insert": (193.25, 144.05), "char_height": 1.8, "attachment_point": 5}
blk.add_mtext('\\A1;222.5mm', dxfattribs=at)
blk = doc.blocks.new('*D15')
at = {"color": 0, "lineweight": -2}
for p, q in [((338, 104.68), (338, 114.14)), ((338.5, 104.18), (338.5, 114.14)), ((336.2, 112.34), (334.4, 112.34)), ((340.3, 112.34), (342.1, 112.34))]:
    blk.add_line(p, q, dxfattribs=at)
at = {"layer": 'Defpoints', "color": 0}
for p in [(338, 112.34), (338, 104.05), (338.5, 103.55)]:
    blk.add_point(p, dxfattribs=at)
at = {"color": 0, "lineweight": -2, "xscale": 1.8, "yscale": 1.8, "zscale": 1.8}
blk.add_blockref('_ClosedBlank', (338, 112.34), dxfattribs=at)
at = {"color": 0, "lineweight": -2, "xscale": 1.8, "yscale": 1.8, "zscale": 1.8, "rotation": 180}
blk.add_blockref('_ClosedBlank', (338.5, 112.34), dxfattribs=at)
at = {"color": 0, "insert": (330.8, 112.34), "char_height": 1.8, "attachment_point": 5}
blk.add_mtext('\\A1;.5mm', dxfattribs=at)
blk = doc.blocks.new('*D20')
at = {"color": 0, "lineweight": -2}
for p, q in [((330.11, 191.39), (322.59, 198.91)), ((331.55, 191.39), (330.11, 191.39))]:
    blk.add_line(p, q, dxfattribs=at)
at = {"layer": 'Defpoints', "color": 0}
for p in [(318.39, 203.12), (321.57, 199.93)]:
    blk.add_point(p, dxfattribs=at)
at = {"color": 0, "lineweight": -2, "xscale": 1.44, "yscale": 1.44, "zscale": 1.44, "rotation": 134.9805878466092}
blk.add_blockref('_ClosedBlank', (321.57, 199.93), dxfattribs=at)
at = {"color": 0, "insert": (335.27, 191.39), "char_height": 1.44, "attachment_point": 5}
blk.add_mtext('\\A1;∅4.50\\PX 90%%d', dxfattribs=at)
blk = doc.blocks.new('*D21')
at = {"color": 0, "lineweight": -2}
for p, q in [((330.65, 212.14), (321.5, 203.03)), ((332.09, 212.14), (330.65, 212.14))]:
    blk.add_line(p, q, dxfattribs=at)
at = {"layer": 'Defpoints', "color": 0}
for p in [(320.48, 202.02), (319.49, 201.03)]:
    blk.add_point(p, dxfattribs=at)
at = {"color": 0, "lineweight": -2, "xscale": 1.44, "yscale": 1.44, "zscale": 1.44, "rotation": 224.8588244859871}
blk.add_blockref('_ClosedBlank', (320.48, 202.02), dxfattribs=at)
at = {"color": 0, "insert": (335.33, 212.14), "char_height": 1.44, "attachment_point": 5}
blk.add_mtext('\\A1;∅1.40', dxfattribs=at)
blk = doc.blocks.new('*D22')
at = {"color": 0, "lineweight": -2}
for p, q in [((82, 106.05), (82, 149.85)), ((319.98, 106.18), (319.98, 149.85)), ((83.8, 148.05), (194.84, 148.05)), ((318.18, 148.05), (207.14, 148.05))]:
    blk.add_line(p, q, dxfattribs=at)
at = {"layer": 'Defpoints', "color": 0}
for p in [(82, 148.05), (82, 105.43), (319.98, 105.55)]:
    blk.add_point(p, dxfattribs=at)
at = {"color": 0, "lineweight": -2, "xscale": 1.8, "yscale": 1.8, "zscale": 1.8, "rotation": 180}
blk.add_blockref('_ClosedBlank', (82, 148.05), dxfattribs=at)
at = {"color": 0, "lineweight": -2, "xscale": 1.8, "yscale": 1.8, "zscale": 1.8}
blk.add_blockref('_ClosedBlank', (319.98, 148.05), dxfattribs=at)
at = {"color": 0, "insert": (200.99, 148.05), "char_height": 1.8, "attachment_point": 5}
blk.add_mtext('\\A1;238.0mm', dxfattribs=at)
blk = doc.blocks.new('*D23')
at = {"color": 0, "lineweight": -2}
for p, q in [((273.39, 107.07), (273.39, 113.24)), ((273.39, 113.24), (275.19, 113.24)), ((271.66, 105.27), (275.19, 105.27)), ((269.12, 103.49), (275.19, 103.49)), ((273.39, 101.69), (273.39, 99.89))]:
    blk.add_line(p, q, dxfattribs=at)
at = {"layer": 'Defpoints', "color": 0}
for p in [(271.04, 105.27), (273.39, 105.27), (268.5, 103.49)]:
    blk.add_point(p, dxfattribs=at)
at = {"color": 0, "lineweight": -2, "xscale": 1.8, "yscale": 1.8, "zscale": 1.8}
for p, rotation in [((273.39, 105.27), 270), ((273.39, 103.49), 90)]:
    blk.add_blockref('_ClosedBlank', p, dxfattribs=dict(at, rotation=rotation))
at = {"color": 0, "insert": (280.29, 113.24), "char_height": 1.8, "attachment_point": 5}
blk.add_mtext('\\A1;1.78mm', dxfattribs=at)
blk = doc.blocks.new('*D25')
at = {"color": 0, "lineweight": -2}
for p, q in [((82, 106.05), (82, 153.85)), ((83.8, 152.05), (203.95, 152.05)), ((336.7, 152.05), (216.55, 152.05)), ((338.5, 104.18), (338.5, 153.85))]:
    blk.add_line(p, q, dxfattribs=at)
at = {"layer": 'Defpoints', "color": 0}
for p in [(82, 152.05), (82, 105.43), (338.5, 103.55)]:
    blk.add_point(p, dxfattribs=at)
at = {"color": 0, "lineweight": -2, "xscale": 1.8, "yscale": 1.8, "zscale": 1.8, "rotation": 180}
blk.add_blockref('_ClosedBlank', (82, 152.05), dxfattribs=at)
at = {"color": 0, "lineweight": -2, "xscale": 1.8, "yscale": 1.8, "zscale": 1.8}
blk.add_blockref('_ClosedBlank', (338.5, 152.05), dxfattribs=at)
at = {"color": 0, "insert": (210.25, 152.05), "char_height": 1.8, "attachment_point": 5}
blk.add_mtext('\\A1;256.5mm', dxfattribs=at)
blk = doc.blocks.new('*D28')
at = {"color": 0, "lineweight": -2}
for p, q in [((318.18, 137.72), (316.38, 137.72)), ((319.98, 138.19), (319.98, 139.52)), ((338.5, 138.19), (338.5, 139.52)), ((340.3, 137.72), (342.1, 137.72))]:
    blk.add_line(p, q, dxfattribs=at)
at = {"layer": 'Defpoints', "color": 0}
for p in [(319.98, 137.56), (338.5, 137.72), (338.5, 137.56)]:
    blk.add_point(p, dxfattribs=at)
at = {"color": 0, "lineweight": -2, "xscale": 1.8, "yscale": 1.8, "zscale": 1.8}
blk.add_blockref('_ClosedBlank', (319.98, 137.72), dxfattribs=at)
at = {"color": 0, "lineweight": -2, "xscale": 1.8, "yscale": 1.8, "zscale": 1.8, "rotation": 180}
blk.add_blockref('_ClosedBlank', (338.5, 137.72), dxfattribs=at)
at = {"color": 0, "insert": (329.24, 137.72), "char_height": 1.8, "attachment_point": 5}
blk.add_mtext('\\A1;18.5180mm', dxfattribs=at)

msp = doc.modelspace()

# ---------------------------------------------------------------- linework, layer by layer
for p, q in [((263.00121, 210.22503), (304.49996, 210.22503)), ((304.49996, 192.82503), (304.49996, 210.22503)), ((304.74996, 209.05003), (337.99996, 209.05003)), ((304.74996, 209.05003), (304.74996, 194.00003)), ((337.99996, 209.05003), (338.49996, 208.55003)), ((337.99996, 194.00003), (337.99996, 209.05003)), ((338.49996, 194.50003), (338.49996, 208.55003)), ((304.74996, 194.00003), (337.99996, 194.00003)), ((337.99996, 194.00003), (338.49996, 194.50003)), ((263.00121, 192.82503), (304.49996, 192.82503)), ((283.75059, 105.26503), (286.50022, 110.02753)), ((282.37577, 107.64628), (283.75059, 105.26503)), ((331.37496, 104.05003), (334.12459, 108.81253)), ((270.89343, 105.26503), (304.49996, 105.26503)), ((304.49996, 87.82503), (304.49996, 105.26503)), ((304.74996, 104.05003), (317.75728, 104.05003)), ((304.74996, 104.05003), (304.74996, 89.00003)), ((322.20671, 104.05003), (337.99996, 104.05003)), ((330.00014, 106.43128), (331.37496, 104.05003)), ((337.99996, 104.05003), (338.49996, 103.55003)), ((337.99996, 89.00003), (337.99996, 104.05003)), ((338.49996, 89.50003), (338.49996, 103.55003)), ((337.99996, 89.00003), (338.49996, 89.50003)), ((263.00121, 87.82503), (304.49996, 87.82503)), ((304.74996, 89.00003), (337.99996, 89.00003))]:
    msp.add_line(p, q)
for points in [[(0, 0), (420, 0), (420, 297), (0, 297)], [(15, 15), (405, 15), (405, 282), (15, 282)]]:
    msp.add_lwpolyline(points, close=True)
for radius in [2.25, 0.7]:
    msp.add_circle((319.982, 201.52503), radius)
for centre, radius, start, end in [((304.74996, 209.30003), 0.25, 180, 270), ((304.74996, 193.75003), 0.25, 90, 180), ((304.74996, 104.30003), 0.25, 180, 270), ((319.982, 111.23865), 7.525, 252.8039036, 287.1960964), ((304.74996, 88.75003), 0.25, 90, 180)]:
    msp.add_arc(centre, radius, start, end)
msp.add_ellipse((268.49996, 201.52503), major_axis=(0, -5.2703), ratio=0.454143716)
at = {"layer": 'CENTER'}
for p, q in [((319.982, 199.30032), (319.982, 203.74974)), ((319.982, 98.68263), (319.982, 105.55003))]:
    msp.add_line(p, q, dxfattribs=at)
at = {"layer": 'CENTERLINE'}
for p, q in [((76.99996, 201.52503), (343.49996, 201.52503)), ((76.99996, 96.52503), (343.49996, 96.52503))]:
    msp.add_line(p, q, dxfattribs=at)
at = {"layer": 'HIDDEN'}
for p, q in [((120.13754, 204.37503), (338.49996, 204.37503)), ((120.13754, 204.30503), (338.49996, 204.30503)), ((120.13754, 198.74503), (338.49996, 198.74503)), ((120.13754, 198.67503), (338.49996, 198.67503)), ((317.75728, 104.05003), (319.282, 102.52532)), ((320.682, 102.52532), (322.20671, 104.05003)), ((319.282, 99.30503), (319.282, 102.52532)), ((319.282, 102.52532), (320.682, 102.52532)), ((320.682, 99.30503), (320.682, 102.52532)), ((120.13754, 99.37503), (338.49996, 99.37503)), ((120.13754, 99.30503), (338.49996, 99.30503)), ((120.13754, 93.74503), (338.49996, 93.74503)), ((120.13754, 93.67503), (338.49996, 93.67503))]:
    msp.add_line(p, q, dxfattribs=at)
msp.add_ellipse((319.982, 99.30503), major_axis=(-0.7, 0), ratio=0.1016, start_param=0, end_param=3.141592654, dxfattribs=at)
at = {"layer": 'TEXT', "color": 7}
for p, q in [((312.80957, 43.525), (312.80957, 46.525)), ((312.80957, 46.525), (317.80957, 46.525)), ((317.80957, 46.525), (322.80957, 46.525)), ((317.80957, 43.525), (317.80957, 46.525)), ((322.80957, 46.525), (330.80957, 46.525)), ((322.80957, 43.525), (322.80957, 46.525)), ((330.80957, 43.525), (330.80957, 46.525)), ((312.80957, 43.525), (317.80957, 43.525)), ((317.80957, 43.525), (322.80957, 43.525)), ((322.80957, 43.525), (330.80957, 43.525))]:
    msp.add_line(p, q, dxfattribs=at)
for radius in [1.25, 0.75]:
    msp.add_circle((315.30957, 45.025), radius, dxfattribs=at)

# ---------------------------------------------------------------- texts
for p in [(283.75059, 107.64628), (331.37496, 106.43128)]:
    msp.add_text('N6', height=1.5875).set_placement(p, align=Align.BOTTOM_CENTER)
for s, insert, char_height, width, attachment_point in [('{\\W0.8;Port Size Verified\\P20, December 2013}', (310.24186, 223.17406), 3, 52.1721357, 5), ('\\A1;%%C{\\H0.7x;\\S17,48mm/17,45mm;}', (283.75059, 70.67503), 2, 10.5482646, 2)]:
    msp.add_mtext(s, dxfattribs=dict(insert=insert, char_height=char_height, width=width, attachment_point=attachment_point))
for s, insert, char_height, width, attachment_point in [('\\A1;Size 1 %%C15,018mm/%%C15,033mm\\P{\\LSize 2 %%C15,048mm/%%C15,063mm}\\PSize 3 %%C15,063mm/%%C15,078mm\\PSize 4 %%C15,118mm/%%C15,138mm', (299.41814, 59.525), 2, 48.5376086, 1), ('-A-', (320.30957, 45.025), 1.5, 1.19634, 5), ('0,01mm', (326.80957, 45.025), 1.5, 6.6720954, 5)]:
    msp.add_mtext(s, dxfattribs=dict(at, insert=insert, char_height=char_height, width=width, attachment_point=attachment_point))

# ---------------------------------------------------------------- dimensions: what is measured, and where the dimension line sits
dim = msp.add_diameter_dim_2p(p1=(319.4858, 201.03128), p2=(320.47819, 202.01878), dimstyle='Standard', override={"dimscale": 8, "dimdec": 2, "dimcen": 0})
dim.commit()
dim.dimension.update_dxf_attribs({"geometry": '*D21', "text_midpoint": (335.3319, 212.14249), "dimtype": 163})
dim = msp.add_diameter_dim_2p(p1=(318.39154, 203.11656), p2=(321.57245, 199.9335), text='<>\\PX 90%%d', dimstyle='Standard', override={"dimscale": 8, "dimdec": 2, "dimcen": 0})
dim.commit()
dim.dimension.update_dxf_attribs({"geometry": '*D20', "text_midpoint": (335.2716, 191.38855), "dimtype": 163})
for base, p1, p2, override, picture, middle in [((81.99996, 152.05003), (338.49996, 103.55003), (81.99996, 105.42503), {"dimscale": 10, "dimdec": 1, "dimpost": 'mm', "dimblk1": 'ClosedBlank', "dimblk2": 'ClosedBlank', "dimsah": 1}, '*D25', (210.24996, 152.05003)), ((81.99996, 148.05003), (319.982, 105.55003), (81.99996, 105.42503), {"dimscale": 10, "dimdec": 1, "dimpost": 'mm', "dimblk1": 'ClosedBlank', "dimblk2": 'ClosedBlank', "dimsah": 1}, '*D22', (200.99098, 148.05003)), ((81.99996, 144.05003), (304.49996, 105.26503), (81.99996, 105.42503), {"dimscale": 10, "dimdec": 1, "dimpost": 'mm', "dimblk1": 'ClosedBlank', "dimblk2": 'ClosedBlank', "dimsah": 1}, '*D14', (193.24996, 144.05003)), ((338.49996, 137.71737), (319.982, 137.56397), (338.49996, 137.56397), {"dimpost": 'mm'}, '*D28', (329.24098, 137.71737))]:
    dim = msp.add_linear_dim(base=base, p1=p1, p2=p2, dimstyle='Standard$0', override=override)
    dim.commit()
    dim.dimension.update_dxf_attribs({"geometry": picture, "text_midpoint": middle})
dim = msp.add_linear_dim(base=(273.38766, 105.26503), p1=(268.49996, 103.48703), p2=(271.03921, 105.26503), angle=90, dimstyle='Standard$0', override={"dimdec": 2, "dimpost": 'mm'})
dim.commit()
dim.dimension.update_dxf_attribs({"geometry": '*D23', "text_midpoint": (280.28766, 113.24372), "dimtype": 160})
dim = msp.add_linear_dim(base=(337.99996, 112.34387), p1=(338.49996, 103.55003), p2=(337.99996, 104.05003), angle=180, dimstyle='Standard$0', override={"dimscale": 10, "dimdec": 1, "dimpost": 'mm', "dimblk1": 'ClosedBlank', "dimblk2": 'ClosedBlank', "dimsah": 1})
dim.commit()
dim.dimension.update_dxf_attribs({"geometry": '*D15', "text_midpoint": (330.79996, 112.34387)})

# ---------------------------------------------------------------- leaders
msp.add_leader([(283.75059, 87.67503), (283.75059, 70.67503)], dimstyle='Standard', override={"dimscale": 1, "dimasz": 2, "dimgap": 0.09, "dimtad": 0, "dimldrblk": 'ClosedBlank'})
msp.add_leader([(321.37496, 89.00003), (321.37496, 60.76401)], dimstyle='Standard', override={"dimscale": 1, "dimasz": 2, "dimgap": 0.09, "dimtad": 0, "dimldrblk": 'ClosedBlank'}, dxfattribs=at)

doc.saveas('drawing.dxf')
